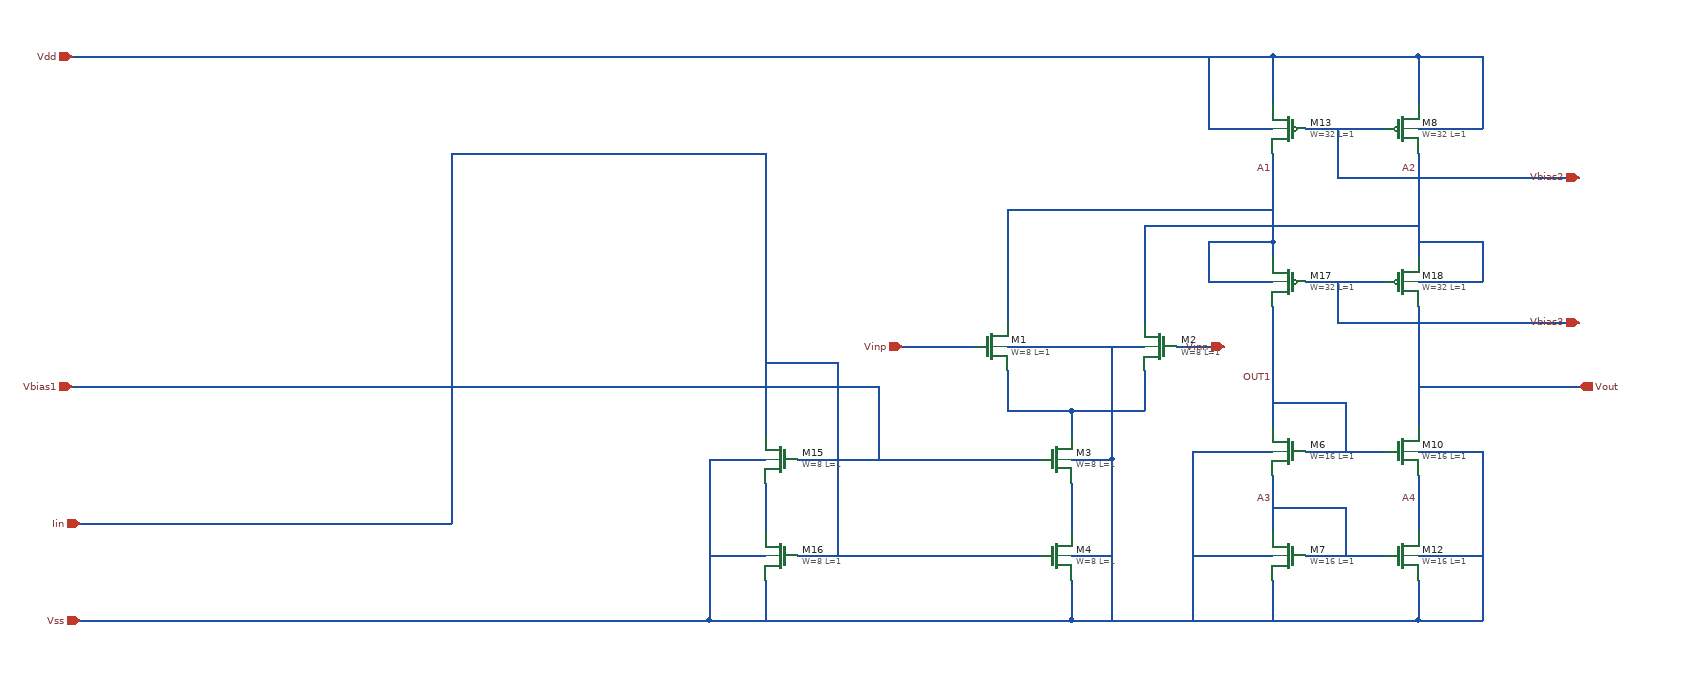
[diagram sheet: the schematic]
v {xschem version=3.1.0 file_version=1.2
}
G {}
K {}
V {}
S {}
E {}
N 1720 -1060 1720 -1050 {
lab=#net1}
N 1720 -1050 1720 -1040 {
lab=#net1}
N 1720 -1040 1720 -1030 {
lab=#net1}
N 1720 -1030 1720 -1020 {
lab=#net1}
N 1720 -1020 1720 -1010 {
lab=#net1}
N 1720 -1010 1800 -1010 {
lab=#net1}
N 1890 -1060 1890 -1010 {
lab=#net1}
N 1800 -1010 1890 -1010 {
lab=#net1}
N 1800 -800 1800 -750 {
lab=Vss}
N 1720 -1200 1720 -1120 {
lab=A1}
N 1720 -1260 1720 -1200 {
lab=A1}
N 2230 -1260 2230 -1200 {
lab=A2}
N 1890 -1220 1890 -1120 {
lab=A2}
N 2050 -1220 2050 -1200 {
lab=A1}
N 2050 -1330 2050 -1220 {
lab=A1}
N 2230 -1330 2230 -1260 {
lab=A2}
N 2050 -1450 2050 -1390 {
lab=Vdd}
N 2230 -1450 2230 -1390 {
lab=Vdd}
N 2050 -1450 2230 -1450 {
lab=Vdd}
N 2090 -1360 2190 -1360 {
lab=Vbias2}
N 1800 -750 2230 -750 {
lab=Vss}
N 1560 -1450 2050 -1450 {
lab=Vdd}
N 1850 -950 1850 -750 {
lab=Vss}
N 1800 -830 1850 -830 {
lab=Vss}
N 1720 -1090 1890 -1090 {
lab=Vss}
N 1800 -1010 1800 -980 {
lab=#net1}
N 1800 -920 1800 -860 {
lab=#net2}
N 1800 -950 1850 -950 {
lab=Vss}
N 2090 -1170 2190 -1170 {
lab=Vbias3}
N 1620 -1090 1680 -1090 {
lab=Vinp}
N 1930 -1090 1990 -1090 {
lab=Vinn}
N 1970 -1360 2050 -1360 {
lab=Vdd}
N 1970 -1450 1970 -1360 {
lab=Vdd}
N 1970 -1170 2050 -1170 {
lab=A1}
N 2230 -1360 2310 -1360 {
lab=Vdd}
N 2310 -1450 2310 -1360 {
lab=Vdd}
N 2230 -1450 2310 -1450 {
lab=Vdd}
N 1590 -1090 1620 -1090 {
lab=Vinp}
N 1420 -920 1420 -860 {
lab=#net3}
N 1420 -800 1420 -750 {
lab=Vss}
N 1510 -1070 1510 -830 {
lab=#net4}
N 1420 -1070 1510 -1070 {
lab=#net4}
N 1350 -830 1420 -830 {
lab=Vss}
N 1350 -950 1420 -950 {
lab=Vss}
N 1350 -950 1350 -820 {
lab=Vss}
N 1350 -820 1350 -750 {
lab=Vss}
N 1350 -750 1800 -750 {
lab=Vss}
N 1460 -830 1760 -830 {
lab=#net4}
N 1460 -950 1760 -950 {
lab=Vbias1}
N 1560 -1040 1560 -950 {
lab=Vbias1}
N 1190 -1040 1560 -1040 {
lab=Vbias1}
N 2130 -1360 2130 -1300 {
lab=Vbias2}
N 1890 -1240 1890 -1220 {
lab=A2}
N 1970 -1220 1970 -1170 {
lab=A1}
N 2230 -1170 2300 -1170 {
lab=A2}
N 2300 -1170 2310 -1170 {
lab=A2}
N 2310 -1220 2310 -1170 {
lab=A2}
N 2130 -1300 2430 -1300 {
lab=Vbias2}
N 2050 -1140 2050 -990 {
lab=OUT1}
N 2050 -800 2050 -750 {
lab=Vss}
N 2230 -920 2230 -860 {
lab=A4}
N 2230 -800 2230 -750 {
lab=Vss}
N 2090 -830 2190 -830 {
lab=A3}
N 2230 -930 2230 -920 {
lab=A4}
N 2230 -1140 2230 -990 {
lab=Vout}
N 2050 -930 2050 -860 {
lab=A3}
N 2140 -1020 2140 -960 {
lab=OUT1}
N 2050 -1020 2140 -1020 {
lab=OUT1}
N 2140 -890 2140 -830 {
lab=A3}
N 2050 -890 2140 -890 {
lab=A3}
N 1950 -960 1950 -750 {
lab=Vss}
N 1950 -830 2050 -830 {
lab=Vss}
N 2230 -960 2310 -960 {
lab=Vss}
N 2310 -960 2310 -750 {
lab=Vss}
N 2230 -830 2310 -830 {
lab=Vss}
N 2230 -1040 2400 -1040 {
lab=Vout}
N 2090 -960 2190 -960 {
lab=OUT1}
N 1950 -960 2050 -960 {
lab=Vss}
N 1420 -1450 1560 -1450 {
lab=Vdd}
N 1850 -1090 1850 -950 {
lab=Vss}
N 1970 -1220 2050 -1220 {
lab=A1}
N 2230 -1220 2310 -1220 {
lab=A2}
N 910 -1040 1190 -1040 {
lab=Vbias1}
N 1030 -750 1350 -750 {
lab=Vss}
N 1030 -1450 1420 -1450 {
lab=Vdd}
N 1420 -1330 1420 -980 {
lab=#net4}
N 1030 -1330 1030 -870 {
lab=Iin}
N 950 -1450 1030 -1450 {
lab=Vdd}
N 560 -1450 950 -1450 {
lab=Vdd}
N 560 -1040 910 -1040 {
lab=Vbias1}
N 570 -870 1030 -870 {
lab=Iin}
N 570 -750 1030 -750 {
lab=Vss}
N 2130 -1170 2130 -1120 {
lab=Vbias3}
N 2130 -1120 2430 -1120 {
lab=Vbias3}
N 2230 -750 2310 -750 {
lab=Vss}
N 2400 -1040 2430 -1040 {
lab=Vout}
N 1890 -1240 2230 -1240 {
lab=A2}
N 1720 -1260 2050 -1260 {
lab=A1}
N 1030 -1330 1420 -1330 {}
C {sky130_fd_pr/nfet_01v8_lvt.sym} 1700 -1090 0 0 {name=M1
L=1
W=8
nf=4
mult=30
ad="'int((nf+1)/2) * W/nf * 0.29'" 
pd="'2*int((nf+1)/2) * (W/nf + 0.29)'"
as="'int((nf+2)/2) * W/nf * 0.29'" 
ps="'2*int((nf+2)/2) * (W/nf + 0.29)'"
nrd="'0.29 / W'" nrs="'0.29 / W'"
sa=0 sb=0 sd=0
model=nfet_01v8_lvt
spiceprefix=X
}
C {sky130_fd_pr/nfet_01v8_lvt.sym} 1910 -1090 0 1 {name=M2
L=1
W=8
nf=4
mult=30
ad="'int((nf+1)/2) * W/nf * 0.29'" 
pd="'2*int((nf+1)/2) * (W/nf + 0.29)'"
as="'int((nf+2)/2) * W/nf * 0.29'" 
ps="'2*int((nf+2)/2) * (W/nf + 0.29)'"
nrd="'0.29 / W'" nrs="'0.29 / W'"
sa=0 sb=0 sd=0
model=nfet_01v8_lvt
spiceprefix=X
}
C {sky130_fd_pr/nfet_01v8_lvt.sym} 1780 -950 0 0 {name=M3
L=1
W=8
nf=2
mult=28
ad="'int((nf+1)/2) * W/nf * 0.29'" 
pd="'2*int((nf+1)/2) * (W/nf + 0.29)'"
as="'int((nf+2)/2) * W/nf * 0.29'" 
ps="'2*int((nf+2)/2) * (W/nf + 0.29)'"
nrd="'0.29 / W'" nrs="'0.29 / W'"
sa=0 sb=0 sd=0
model=nfet_01v8_lvt
spiceprefix=X
}
C {sky130_fd_pr/nfet_01v8_lvt.sym} 1780 -830 0 0 {name=M4
L=1
W=8
nf=2
mult=28
ad="'int((nf+1)/2) * W/nf * 0.29'" 
pd="'2*int((nf+1)/2) * (W/nf + 0.29)'"
as="'int((nf+2)/2) * W/nf * 0.29'" 
ps="'2*int((nf+2)/2) * (W/nf + 0.29)'"
nrd="'0.29 / W'" nrs="'0.29 / W'"
sa=0 sb=0 sd=0
model=nfet_01v8_lvt
spiceprefix=X
}
C {sky130_fd_pr/nfet_01v8_lvt.sym} 2210 -960 0 0 {name=M10
L=1
W=16
nf=8
mult=12
ad="'int((nf+1)/2) * W/nf * 0.29'" 
pd="'2*int((nf+1)/2) * (W/nf + 0.29)'"
as="'int((nf+2)/2) * W/nf * 0.29'" 
ps="'2*int((nf+2)/2) * (W/nf + 0.29)'"
nrd="'0.29 / W'" nrs="'0.29 / W'"
sa=0 sb=0 sd=0
model=nfet_01v8_lvt
spiceprefix=X
}
C {sky130_fd_pr/nfet_01v8_lvt.sym} 2210 -830 0 0 {name=M12
L=1
W=16
nf=8
mult=10
ad="'int((nf+1)/2) * W/nf * 0.29'" 
pd="'2*int((nf+1)/2) * (W/nf + 0.29)'"
as="'int((nf+2)/2) * W/nf * 0.29'" 
ps="'2*int((nf+2)/2) * (W/nf + 0.29)'"
nrd="'0.29 / W'" nrs="'0.29 / W'"
sa=0 sb=0 sd=0
model=nfet_01v8_lvt
spiceprefix=X
}
C {sky130_fd_pr/nfet_01v8_lvt.sym} 1440 -950 0 1 {name=M15
L=1
W=8
nf=2
mult=2
ad="'int((nf+1)/2) * W/nf * 0.29'" 
pd="'2*int((nf+1)/2) * (W/nf + 0.29)'"
as="'int((nf+2)/2) * W/nf * 0.29'" 
ps="'2*int((nf+2)/2) * (W/nf + 0.29)'"
nrd="'0.29 / W'" nrs="'0.29 / W'"
sa=0 sb=0 sd=0
model=nfet_01v8_lvt
spiceprefix=X
}
C {sky130_fd_pr/nfet_01v8_lvt.sym} 1440 -830 0 1 {name=M16
L=1
W=8
nf=2
mult=2
ad="'int((nf+1)/2) * W/nf * 0.29'" 
pd="'2*int((nf+1)/2) * (W/nf + 0.29)'"
as="'int((nf+2)/2) * W/nf * 0.29'" 
ps="'2*int((nf+2)/2) * (W/nf + 0.29)'"
nrd="'0.29 / W'" nrs="'0.29 / W'"
sa=0 sb=0 sd=0
model=nfet_01v8_lvt
spiceprefix=X
}
C {sky130_fd_pr/pfet_01v8_lvt.sym} 2070 -1360 0 1 {name=M13
L=1
W=32
nf=8
mult=30
ad="'int((nf+1)/2) * W/nf * 0.29'" 
pd="'2*int((nf+1)/2) * (W/nf + 0.29)'"
as="'int((nf+2)/2) * W/nf * 0.29'" 
ps="'2*int((nf+2)/2) * (W/nf + 0.29)'"
nrd="'0.29 / W'" nrs="'0.29 / W'"
sa=0 sb=0 sd=0
model=pfet_01v8_lvt
spiceprefix=X
}
C {sky130_fd_pr/pfet_01v8_lvt.sym} 2070 -1170 0 1 {name=M17
L=1
W=32
nf=8
mult=24
ad="'int((nf+1)/2) * W/nf * 0.29'" 
pd="'2*int((nf+1)/2) * (W/nf + 0.29)'"
as="'int((nf+2)/2) * W/nf * 0.29'" 
ps="'2*int((nf+2)/2) * (W/nf + 0.29)'"
nrd="'0.29 / W'" nrs="'0.29 / W'"
sa=0 sb=0 sd=0
model=pfet_01v8_lvt
spiceprefix=X
}
C {sky130_fd_pr/pfet_01v8_lvt.sym} 2210 -1170 0 0 {name=M18
L=1
W=32
nf=8
mult=24
ad="'int((nf+1)/2) * W/nf * 0.29'" 
pd="'2*int((nf+1)/2) * (W/nf + 0.29)'"
as="'int((nf+2)/2) * W/nf * 0.29'" 
ps="'2*int((nf+2)/2) * (W/nf + 0.29)'"
nrd="'0.29 / W'" nrs="'0.29 / W'"
sa=0 sb=0 sd=0
model=pfet_01v8_lvt
spiceprefix=X
}
C {sky130_fd_pr/nfet_01v8_lvt.sym} 2070 -960 0 1 {name=M6
L=1
W=16
nf=8
mult=12
ad="'int((nf+1)/2) * W/nf * 0.29'" 
pd="'2*int((nf+1)/2) * (W/nf + 0.29)'"
as="'int((nf+2)/2) * W/nf * 0.29'" 
ps="'2*int((nf+2)/2) * (W/nf + 0.29)'"
nrd="'0.29 / W'" nrs="'0.29 / W'"
sa=0 sb=0 sd=0
model=nfet_01v8_lvt
spiceprefix=X
}
C {sky130_fd_pr/nfet_01v8_lvt.sym} 2070 -830 0 1 {name=M7
L=1
W=16
nf=8
mult=10
ad="'int((nf+1)/2) * W/nf * 0.29'" 
pd="'2*int((nf+1)/2) * (W/nf + 0.29)'"
as="'int((nf+2)/2) * W/nf * 0.29'" 
ps="'2*int((nf+2)/2) * (W/nf + 0.29)'"
nrd="'0.29 / W'" nrs="'0.29 / W'"
sa=0 sb=0 sd=0
model=nfet_01v8_lvt
spiceprefix=X
}
C {sky130_fd_pr/pfet_01v8_lvt.sym} 2210 -1360 0 0 {name=M8
L=1
W=32
nf=8
mult=30
ad="'int((nf+1)/2) * W/nf * 0.29'" 
pd="'2*int((nf+1)/2) * (W/nf + 0.29)'"
as="'int((nf+2)/2) * W/nf * 0.29'" 
ps="'2*int((nf+2)/2) * (W/nf + 0.29)'"
nrd="'0.29 / W'" nrs="'0.29 / W'"
sa=0 sb=0 sd=0
model=pfet_01v8_lvt
spiceprefix=X
}
C {iopin.sym} 560 -1450 2 0 {name=p1 lab=Vdd}
C {ipin.sym} 560 -1040 0 0 {name=p2 lab=Vbias1}
C {ipin.sym} 570 -870 0 0 {name=p3 lab=Iin}
C {ipin.sym} 1590 -1090 0 0 {name=p8 lab=Vinp}
C {ipin.sym} 1990 -1090 2 0 {name=p5 lab=Vinn}
C {ipin.sym} 2430 -1300 2 0 {name=p6 lab=Vbias2}
C {ipin.sym} 2430 -1120 2 0 {name=p9 lab=Vbias3}
C {opin.sym} 2430 -1040 0 0 {name=p4 lab=Vout}
C {iopin.sym} 570 -750 2 0 {name=p7 lab=Vss}
C {lab_wire.sym} 2050 -1310 0 0 {name=p10 sig_type=std_logic lab=A1}
C {lab_wire.sym} 2230 -1310 0 0 {name=p11 sig_type=std_logic lab=A2}
C {lab_wire.sym} 2050 -1050 0 0 {name=p12 sig_type=std_logic lab=OUT1}
C {lab_wire.sym} 2050 -900 0 0 {name=p13 sig_type=std_logic lab=A3}
C {lab_wire.sym} 2230 -900 0 0 {name=p14 sig_type=std_logic lab=A4}
